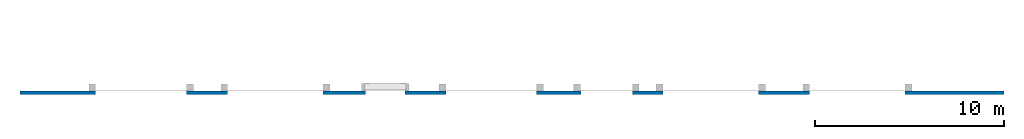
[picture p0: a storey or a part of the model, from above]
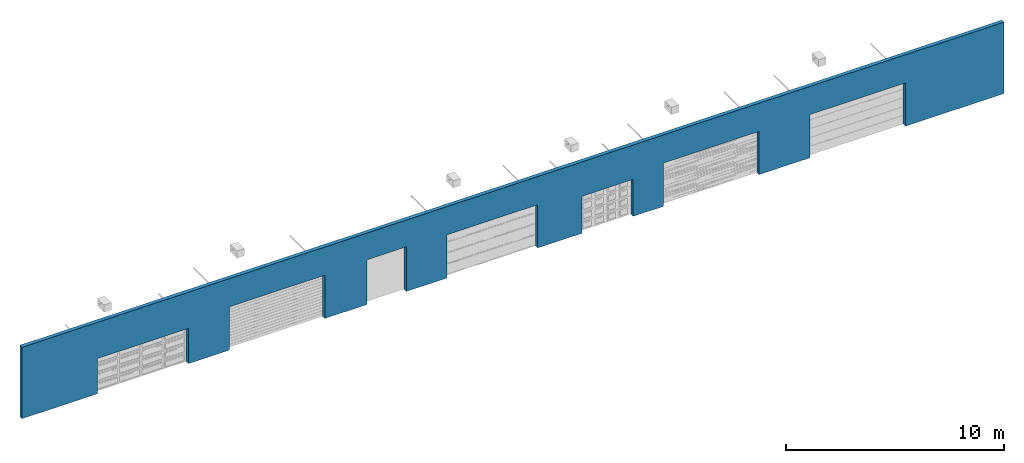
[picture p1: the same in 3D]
Properties of the parts of a building model (IFC2X3)

# File
Description: ViewDefinition [CoordinationView_V2.0]
Time: 2019-07-04T16:06:48
Written by: The EXPRESS Data Manager Version 5.02.0100.07 : 28 Aug 2013
Made in: 20160225_1515(x64) - Exporter 17.0.416.0 - Alternate UI 17.12.14.0
Comment: STEP Physical File produced by: The EXPRESS Data Manager Version 5.02.0100.07 : 28 Aug 2013 * Module: EDMstepFileFactory/EDMstandAlone * Creation date: Thu Jul 04 16:06:48 2019 * Host: A2K_QLD_T017 * Database: C:\Users\CHRIST~1\AppData\Local\Temp\{3117A69C-C211-47D7-97E1-55E85D112196}\ifc * Database version: 5507 * Database creation date: Thu Jul 04 16:06:45 2019 * Schema: IFC2X3 * Model: DataRepository.ifc * Model creation date: Thu Jul 04 16:06:45 2019 * Header model: DataRepository.ifc_HeaderModel * Header model creation date: Thu Jul 04 16:06:45 2019 * EDMuser: sdai-user * EDMgroup: sdai-group * License ID and type: 5605 : Permanent license. Expiry date: * EDMstepFileFactory options: 020000

# IfcSite, Default
RefLatitude: 42, 24, 53, 508911; RefLongitude: -71, -15, -29, -58837; RefElevation: 0 mm

# IfcBuilding
Pset_BuildingCommon - NumberOfStoreys: 1

# IfcBuildingStorey, Level 1
LongName: Level 1; Elevation: 0 mm

# IfcBuildingElementProxy: Standard, X-Door-Panel-Steel Line-Roller:Standard:18887
In: Level 1
Type - Material: Steel, Metal Sheeting-Steel Line-COLORBOND®-Wilderness
Pset_BuildingElementProxyCommon - Reference: Standard

# IfcDoor: 21.27 PLD (2)
In: Level 1
Type - ParameterTakesPrecedence: no; Sizeable: no; Material: Clipsal White Electric (WE), ClearanceZone, Colorbond Bushland - Steelline Doors, Zincalume - Steelline Doors
Pset_DoorCommon - IsExternal: yes; Reference: 21.27 PLD
Pset_ManufacturerTypeInformation - Manufacturer: Steel-Line Garage Doors
Name | OverallHeight (mm) | OverallWidth (mm)
Door-Garage-Steel Line-Sectional-Ranch:21.27 PLD:8716 | 1970 | 4810
Door-Garage-Steel Line-Sectional-Heritage:21.27 PLD:31445 | 2070 | 2710

# IfcDoor: 24.505PLD (3)
In: Level 1
Type - ParameterTakesPrecedence: no; Sizeable: no; Material: Clipsal White Electric (WE), ClearanceZone, Colorbond Bushland - Steelline Doors, Zincalume - Steelline Doors
OverallHeight: 2420 mm; OverallWidth: 5050 mm
Pset_DoorCommon - IsExternal: yes; Reference: 24.505PLD
Pset_ManufacturerTypeInformation - Manufacturer: Steel-Line Garage Doors
Name
Door-Garage-Steel Line-Sectional-Slim Line:24.505PLD:14048
Door-Garage-Steel Line-Sectional-Glacier:24.505PLD:36790
Door-Garage-Steel Line-Sectional-Flat Line:24.505PLD:42097

# IfcDoor: 24.505PLD, Door-Garage-Steel Line-Sectional-Inspirations:24.505PLD:25182
In: Level 1
Type - ParameterTakesPrecedence: no; Sizeable: no; Material: Steel-Line - Acrylic - Light Grey Tint (AN-2332), Steel-Line - Colorbond Bushland, Clipsal White Electric (WE), ClearanceZone, Steel-Line Tracks - Zincalume
OverallHeight: 2420 mm; OverallWidth: 4800 mm
Pset_DoorCommon - IsExternal: yes; Reference: 24.505PLD
Pset_ManufacturerTypeInformation - Manufacturer: Steel-Line Garage Doors

# IfcDoor: Standard, Door-Roller-Steel Line-Standard:Standard:18885
In: Level 1
Type - ParameterTakesPrecedence: no; Sizeable: no; Material: Metal-Black Powdercoat, Steel, ClearanceZone
OverallHeight: 2500 mm; OverallWidth: 2100 mm
Pset_DoorCommon - Reference: Standard; IsExternal: no
Pset_ManufacturerTypeInformation - Manufacturer: Steel-Line Garage Doors

# IfcWallStandardCase: Basic Wall:Wall 1, Basic Wall:Wall 1:2445
In: Level 1
Type - PredefinedType: STANDARD; Material: Default Wall 200 mm
Pset_WallCommon - Reference: Wall 1; LoadBearing: no; ExtendToStructure: no; IsExternal: yes
